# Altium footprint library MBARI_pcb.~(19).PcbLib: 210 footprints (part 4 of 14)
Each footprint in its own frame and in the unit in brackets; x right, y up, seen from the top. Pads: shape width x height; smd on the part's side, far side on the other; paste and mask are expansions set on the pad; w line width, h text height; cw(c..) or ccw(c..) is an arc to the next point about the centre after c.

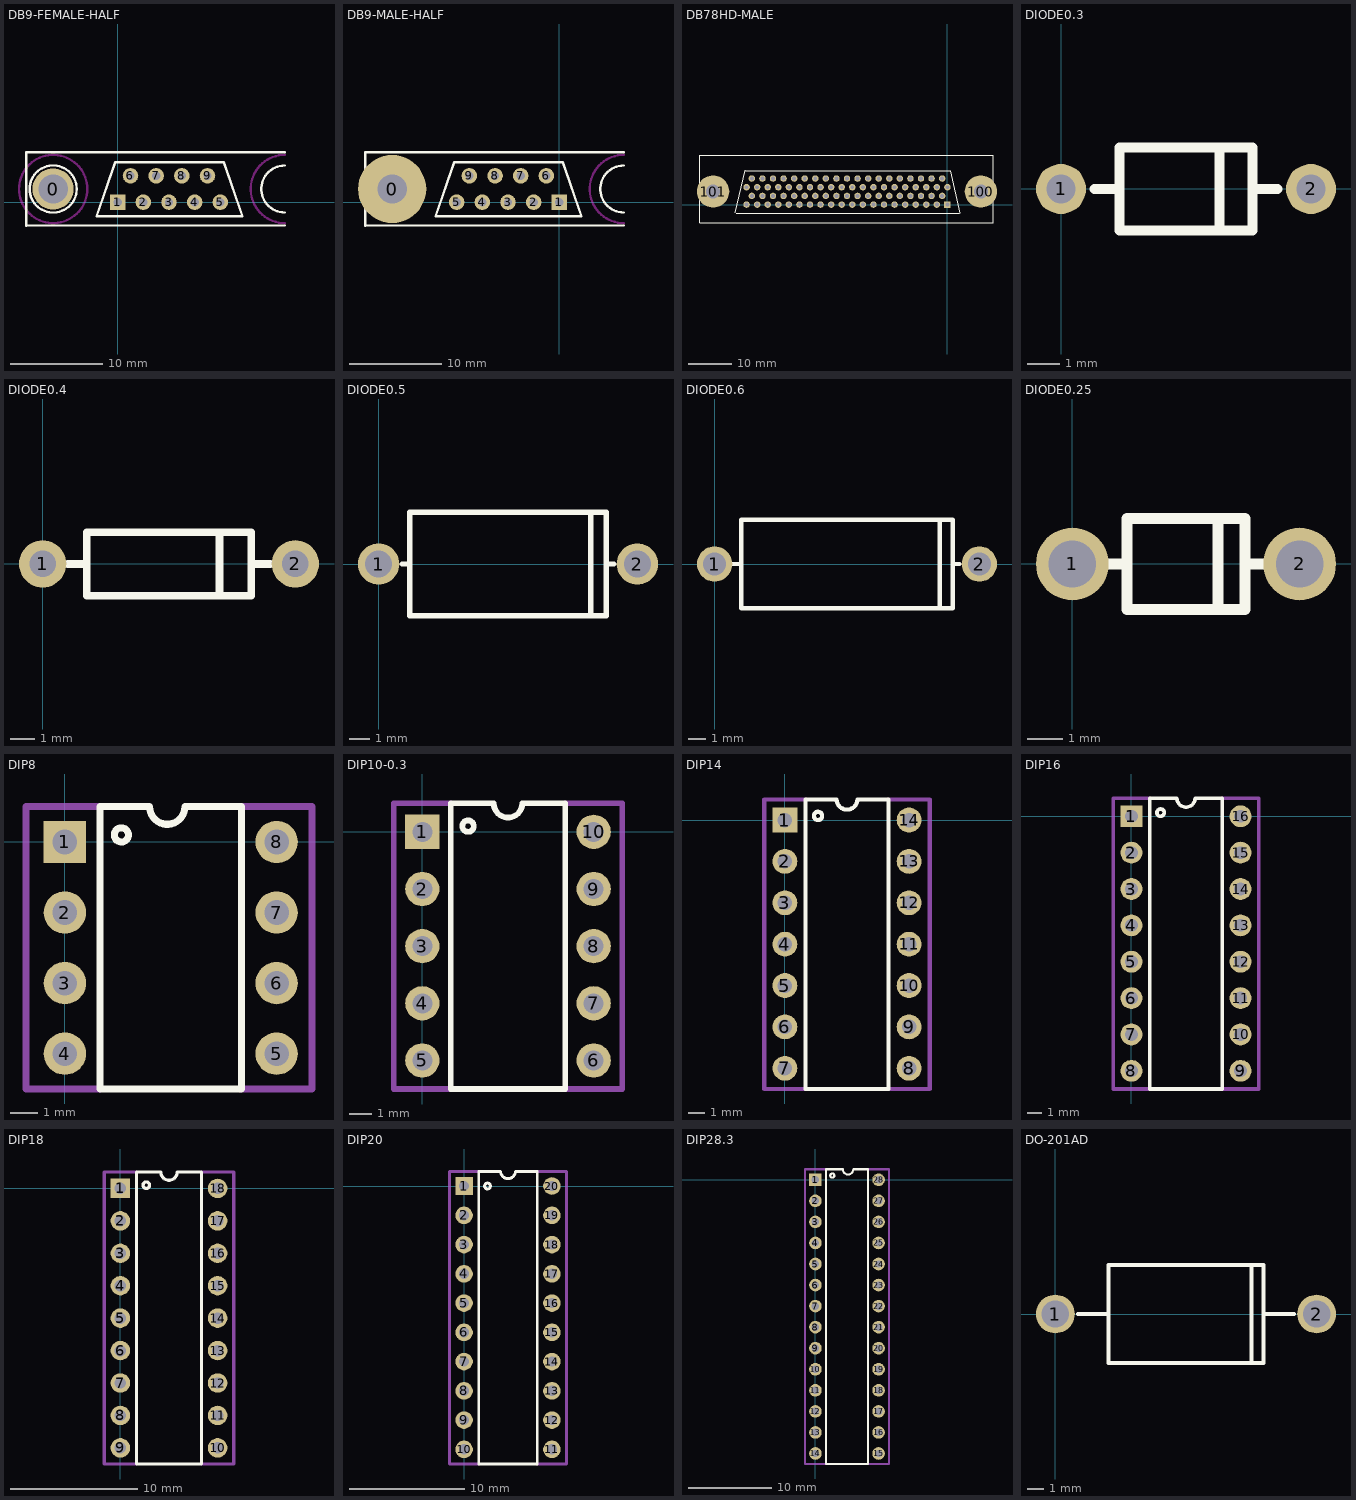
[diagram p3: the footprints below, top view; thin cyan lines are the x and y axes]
## DB9-FEMALE-HALF [mil]
pads (10):
  round 175 hole 125: 0(-274,56)
  rect 66x66 hole 35: 1(0,0)
  round 66 hole 35: 2(109,0) 3(218,0) 4(327,0) 5(436,0) 6(54.5,112) 7(163.5,112) 8(272.5,112) 9(381.5,112)
TopOverlay:
  circle w10: c-274,56 r100
  lines w8: -388.5,-99.5 710,-99.5
  lines w10: -388.5,-99.5 -388.5,211.5 710,211.5 ; 710,-44 cw(c710,56) 710,156 ; -90,-60 530,-60 450,170 -10,170 -90,-60
KeepOutLayer:
  circle w10: c-274,56 r145
  lines w10: 710,-89 cw(c710,56) 710,201

## DB9-MALE-HALF [mil]
pads (10):
  round 290 hole 125: 0(-710,56)
  rect 66x66 hole 35: 1(0,0)
  round 66 hole 35: 2(-109,0) 3(-218,0) 4(-327,0) 5(-436,0) 6(-55,112) 7(-164,112) 8(-273,112) 9(-382,112)
TopOverlay:
  circle w10: c-710,56 r100
  lines w8: -824.5,-99.5 274,-99.5
  lines w10: -824.5,-99.5 -824.5,211.5 274,211.5 ; 274,-44 cw(c274,56) 274,156 ; -526,-60 94,-60 14,170 -446,170 -526,-60
KeepOutLayer:
  lines w10: 274,-89 cw(c274,56) 274,201

## DB78HD-MALE [mil]
pads (80):
  rect 58x58 hole 35: 1(0,0)
  round 58 hole 35: 2(-95,0) 3(-190,0) 4(-285,0) 5(-380,0) 6(-475,0) 7(-570,0) 8(-665,0) 9(-760,0) 10(-855,0) 11(-950,0) 12(-1045,0) 13(-1140,0) 14(-1235,0) 15(-1330,0) 16(-1425,0) 17(-1520,0) 18(-1615,0) 19(-1710,0) 20(-1805,0) 21(-47.5,78) 22(-142.5,78) 23(-237.5,78) 24(-332.5,78) 25(-427.5,78) 26(-522.5,78) 27(-617.5,78) 28(-712.5,78) 29(-807.5,78) 30(-902.5,78) 31(-997.5,78) 32(-1092.5,78) 33(-1187.5,78) 34(-1282.5,78) 35(-1377.5,78) 36(-1472.5,78) 37(-1567.5,78) 38(-1662.5,78) 39(-1757.5,78) 40(0,156) 41(-95,156) 42(-190,156) 43(-285,156) 44(-380,156) 45(-475,156) 46(-570,156) 47(-665,156) 48(-760,156) 49(-855,156) 50(-950,156) 51(-1045,156) 52(-1140,156) 53(-1235,156) 54(-1330,156) 55(-1425,156) 56(-1520,156) 57(-1615,156) 58(-1710,156) 59(-1805,156) 60(-47.5,234) 61(-142.5,234) 62(-237.5,234) 63(-332.5,234) 64(-427.5,234) 65(-522.5,234) 66(-617.5,234) 67(-712.5,234) 68(-807.5,234) 69(-902.5,234) 70(-997.5,234) 71(-1092.5,234) 72(-1187.5,234) 73(-1282.5,234) 74(-1377.5,234) 75(-1472.5,234) 76(-1567.5,234) 77(-1662.5,234) 78(-1757.5,234)
  round 290 hole 125: 100(300.5,117) 101(-2105.5,117)
TopOverlay:
  lines w10: -1905,-73 -1815,307 ; -1897,-77.5 108,-76 ; -1815,305 27,305 110,-76 ; -2228,-163 410,-163 410,443 -2228,443 -2228,-163

## DIODE0.3 [mil]
pads (2):
  round 60 hole 35: 1(0,0) 2(300,0)
TopOverlay:
  lines w12: 40,0 70,0 ; 190,-50 190,50 ; 230,0 260,0 ; 70,-50 70,50 230,50 230,-50 70,-50

## DIODE0.4 [mil]
pads (2):
  round 75 hole 42: 1(0,0) 2(400,0)
TopOverlay:
  lines w12: 40,-0.2 70,-0.2 ; 280,-50.2 280,49.8 ; 330,-0.2 360,-0.2 ; 70,-50.2 70,49.8 330,49.8 330,-50.2 70,-50.2

## DIODE0.5 [mil]
pads (2):
  round 80 hole 52: 1(0,0) 2(500,0)
TopOverlay:
  lines w10: 45,0 60,0 ; 410,-100 410,100 ; 440,0 455,0 ; 60,0 60,-100 440,-100 440,100 60,100 60,0

## DIODE0.6 [mil]
pads (2):
  round 80 hole 52: 1(0,0) 2(600,0)
TopOverlay:
  lines w10: 40,0 55,0 ; 510,-100 510,100 ; 540,0 555,0 ; 60,-100 540,-100 540,100 60,100 60,0 60,-100

## DIODE0.25 [mil]
pads (2):
  round 80 hole 52: 1(0,0) 2(250,0)
TopOverlay:
  lines w12: 40,0 60,0 ; 160,-50 160,50 ; 190,0 210,0 ; 60,-50 190,-50 190,50 60,50 60,-50

## DIP8 [mil]
pads (8):
  rect 60x60 hole 35: 1(0,0)
  round 60 hole 35: 2(0,-100) 3(0,-200) 4(0,-300) 5(300,-300) 6(300,-200) 7(300,-100) 8(300,0)
TopOverlay:
  circle w10: c80,10 r10
  lines w10: 50,-350 50,50 120,50 ccw(c145,50) 170,50 250,50 250,-350 50,-350
Mechanical1:
  lines w10: 50,-350 -55,-350 -55,50 50,50 ; 249,-350 350,-350 350,50 249,50

## DIP10-0.3 [mil] "10 pin DIP 0.3\" spacing"
pads (10):
  rect 60x60 hole 35: 1(0,0)
  round 60 hole 35: 2(0,-100) 3(0,-200) 4(0,-300) 5(0,-400) 6(300,-400) 7(300,-300) 8(300,-200) 9(300,-100) 10(300,0)
TopOverlay:
  circle w10: c80,10 r10
  lines w10: 50,-450 50,50 125,50 ccw(c150,50) 175,50 250,50 250,-450 50,-450
Mechanical1:
  lines w10: 50,-450 -50,-450 -50,50 50,50 ; 250,-450 350,-450 350,50 250,50

## DIP14 [mil]
pads (14):
  rect 60x60 hole 35: 1(0,0)
  round 60 hole 35: 2(0,-100) 3(0,-200) 4(0,-300) 5(0,-400) 6(0,-500) 7(0,-600) 8(300,-600) 9(300,-500) 10(300,-400) 11(300,-300) 12(300,-200) 13(300,-100) 14(300,0)
TopOverlay:
  circle w10: c80,10 r10
  lines w10: 50,-650 250,-650 250,50 175,50 cw(c150,50) 125,50 50,50 50,-650
Mechanical1:
  lines w10: 50,-650 -50,-650 -50,50 50,50 ; 250,-650 350,-650 350,50 250,50

## DIP16 [mil]
pads (16):
  rect 60x60 hole 35: 1(0,0)
  round 60 hole 35: 2(0,-100) 3(0,-200) 4(0,-300) 5(0,-400) 6(0,-500) 7(0,-600) 8(0,-700) 9(300,-700) 10(300,-600) 11(300,-500) 12(300,-400) 13(300,-300) 14(300,-200) 15(300,-100) 16(300,0)
TopOverlay:
  circle w10: c80,10 r10
  lines w10: 50,-750 250,-750 250,50 175,50 cw(c150,50) 125,50 50,50 50,-750
Mechanical1:
  lines w10: 50,-750 -50,-750 -50,50 50,50 ; 250,-750 350,-750 350,50 250,50

## DIP18 [mil]
pads (18):
  rect 60x60 hole 35: 1(0,0)
  round 60 hole 35: 2(0,-100) 3(0,-200) 4(0,-300) 5(0,-400) 6(0,-500) 7(0,-600) 8(0,-700) 9(0,-800) 10(300,-800) 11(300,-700) 12(300,-600) 13(300,-500) 14(300,-400) 15(300,-300) 16(300,-200) 17(300,-100) 18(300,0)
TopOverlay:
  circle w10: c80,10 r10
  lines w10: 175,50.27 cw(c150,50.27) 125,50.27 50,50.27 50,-849.73 249.45,-849.73 ; 175,50.27 250,50.27 250,-849.17
Mechanical1:
  lines w10: 49.73,-849.73 -50,-849.73 -50,50.27 50,50.27 ; 250,50.27 350,50.27 350,-849.73 250.28,-849.73

## DIP20 [mil]
pads (20):
  rect 60x60 hole 35: 1(0,0)
  round 60 hole 35: 2(0,-100) 3(0,-200) 4(0,-300) 5(0,-400) 6(0,-500) 7(0,-600) 8(0,-700) 9(0,-800) 10(0,-900) 11(300,-900) 12(300,-800) 13(300,-700) 14(300,-600) 15(300,-500) 16(300,-400) 17(300,-300) 18(300,-200) 19(300,-100) 20(300,0)
TopOverlay:
  circle w10: c80,0 r10
  lines w10: 50,50 50,-950 250,-950 250,50 175,50.27 ; 50,50.27 125,50.27 ccw(c150,50.27) 175,50.27
Mechanical1:
  lines w10: 50,-950 -50,-950 -50,50 50,50 ; 250,-950 350,-950 350,50 250,50

## DIP28.3 [mil]
pads (28):
  rect 60x60 hole 35: 1(0,0)
  round 60 hole 35: 2(0,-100) 3(0,-200) 4(0,-300) 5(0,-400) 6(0,-500) 7(0,-600) 8(0,-700) 9(0,-800) 10(0,-900) 11(0,-1000) 12(0,-1100) 13(0,-1200) 14(0,-1300) 15(300,-1300) 16(300,-1200) 17(300,-1100) 18(300,-1000) 19(300,-900) 20(300,-800) 21(300,-700) 22(300,-600) 23(300,-500) 24(300,-400) 25(300,-300) 26(300,-200) 27(300,-100) 28(300,0)
TopOverlay:
  circle w10: c80,20 r10
  lines w10: 50,-1350 250,-1350 250,50 180,50 cw(c155,50) 130,50 50,50 50,-1350
Mechanical1:
  lines w10: 50,-1350 -50,-1350 -50,50 50,50 ; 250,-1350 350,-1350 350,50 250,50

## DO-201AD [mil]
pads (2):
  round 95 hole 67: 1(0,0) 2(640,0)
TopOverlay:
  lines w10: 55,0 130,0 ; 480,-120 480,120 ; 510,0 585,0 ; 130,0 130,120 510,120 510,-120 130,-120 130,0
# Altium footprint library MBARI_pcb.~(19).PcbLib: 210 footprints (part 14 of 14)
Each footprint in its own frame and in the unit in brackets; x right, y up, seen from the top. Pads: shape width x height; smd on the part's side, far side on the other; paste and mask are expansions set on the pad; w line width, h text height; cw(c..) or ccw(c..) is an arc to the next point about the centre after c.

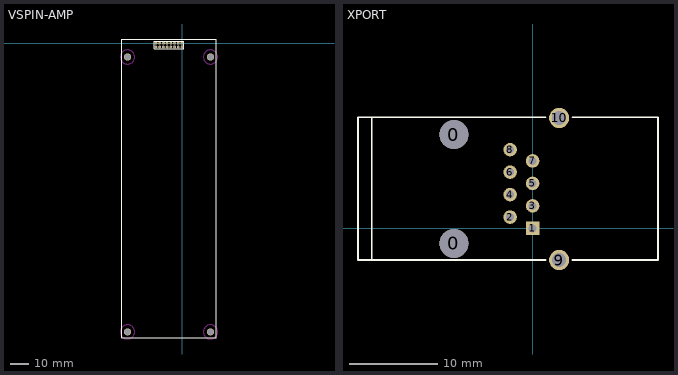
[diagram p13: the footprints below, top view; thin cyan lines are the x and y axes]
## VSPIN-AMP [mil]
pads (20):
  round 150 hole 125: 0(-1150,-6090) 0(-1150,-290) 0(600,-6090) 0(600,-290)
  rect 60x60 hole 35: 1(0,0)
  round 60 hole 35: 2(0,-78.74) 3(-78.74,0) 4(-78.74,-78.74) 5(-157.48,0) 6(-157.48,-78.74) 7(-236.22,0) 8(-236.22,-78.74) 9(-314.96,0) 10(-314.96,-78.74) 11(-393.7,0) 12(-393.7,-78.74) 13(-472.44,0) 14(-472.44,-78.74) 15(-551.18,0) 16(-551.18,-78.74)
TopOverlay:
  lines w8: -590,-120 40,-120 40,40 -590,40 -590,-120
  lines w10: -1275,-6210 725,-6210 725,90 -1275,90 -1275,-6210
BottomOverlay:
  text "Amp Logic" at -140,-170 h45
KeepOutLayer:
  circle w10: c-1150,-290 r150
  circle w10: c600,-290 r150
  circle w10: c-1150,-6090 r150
  circle w10: c600,-6090 r150

## XPORT [mil]
pads (12):
  round 128 hole 128 unplated: 0(-350,-67) 0(-350,417)
  rect 60x60 hole 35: 1(0,0)
  round 60 hole 35: 2(-100,50) 3(0,100) 4(-100,150) 5(0,200) 6(-100,250) 7(0,300) 8(-100,350)
  round 90 hole 63: 9(118,-141) 10(118,491)
TopOverlay:
  lines w7: -715,-141 -715,494
  lines w8: 58,-141 -777,-141 -777,-121 -777,494 58,494 ; 178,-141 558,-141 558,494 178,494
